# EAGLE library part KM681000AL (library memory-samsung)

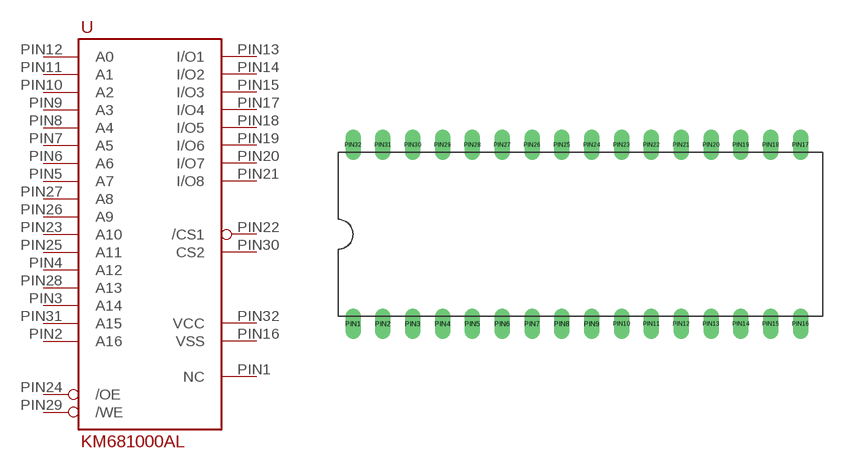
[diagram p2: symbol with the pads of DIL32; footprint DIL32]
Designator prefix -

## KM681000AL  [DIL32]
PIN1  NC  nc
PIN2  A16  in
PIN3  A14  in
PIN4  A12  in
PIN5  A7  in
PIN6  A6  in
PIN7  A5  in
PIN8  A4  in
PIN9  A3  in
PIN10  A2  in
PIN11  A1  in
PIN12  A0  in
PIN13  I/O1
PIN14  I/O2
PIN15  I/O3
PIN16  VSS  pwr
PIN17  I/O4
PIN18  I/O5
PIN19  I/O6
PIN20  I/O7
PIN21  I/O8
PIN22  /CS1  in
PIN23  A10  in
PIN24  /OE  in
PIN25  A11  in
PIN26  A9  in
PIN27  A8  in
PIN28  A13  in
PIN29  /WE  in
PIN30  CS2  in
PIN31  A15  in
PIN32  VCC  pwr

## Footprint DIL32 (pad centres in mm)
drill 0.8 long: PIN1 -17.78,-7.62; PIN2 -15.24,-7.62; PIN3 -12.7,-7.62; PIN4 -10.16,-7.62; PIN5 -7.62,-7.62; PIN6 -5.08,-7.62; PIN7 -2.54,-7.62; PIN8 0,-7.62; PIN9 2.54,-7.62; PIN10 5.08,-7.62; PIN11 7.62,-7.62; PIN12 10.16,-7.62; PIN13 12.7,-7.62; PIN14 15.24,-7.62; PIN15 17.78,-7.62; PIN16 20.32,-7.62; PIN17 20.32,7.62; PIN18 17.78,7.62; PIN19 15.24,7.62; PIN20 12.7,7.62; PIN21 10.16,7.62; PIN22 7.62,7.62; PIN23 5.08,7.62; PIN24 2.54,7.62; PIN25 0,7.62; PIN26 -2.54,7.62; PIN27 -5.08,7.62; PIN28 -7.62,7.62; PIN29 -10.16,7.62; PIN30 -12.7,7.62; PIN31 -15.24,7.62; PIN32 -17.78,7.62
